VERSION 5.7 ;
  NOWIREEXTENSIONATPIN ON ;
  DIVIDERCHAR "/" ;
  BUSBITCHARS "[]" ;
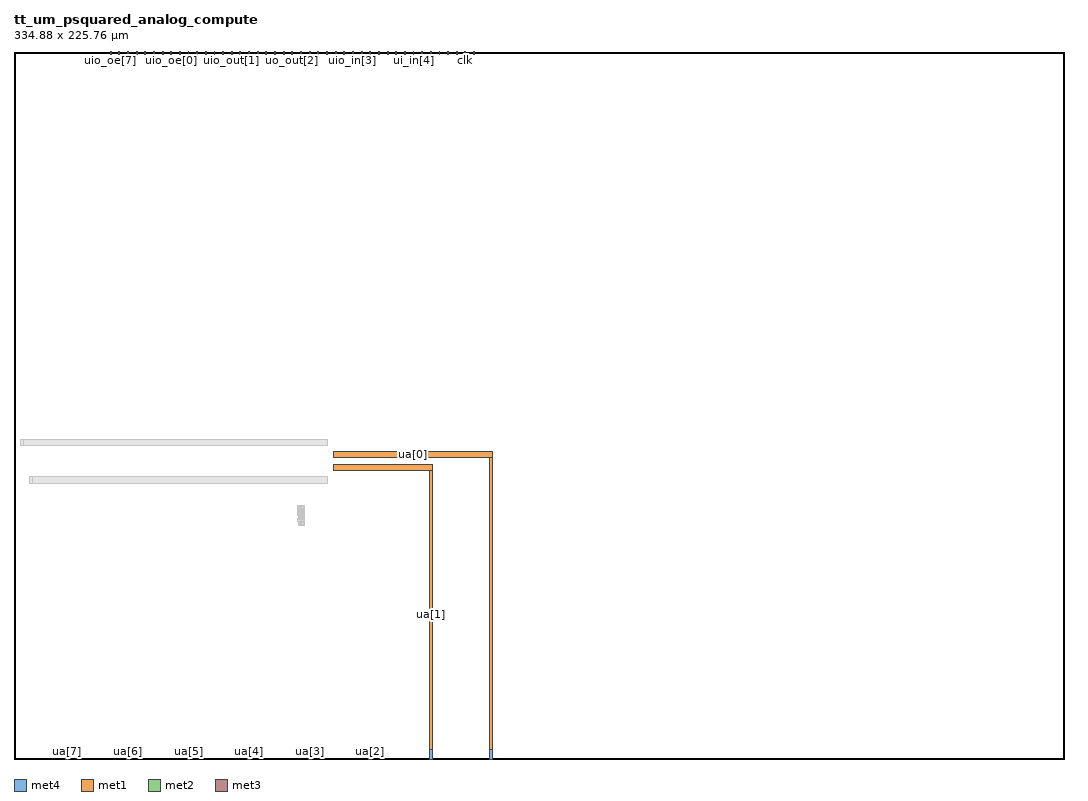
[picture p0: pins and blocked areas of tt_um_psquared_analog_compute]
MACRO tt_um_psquared_analog_compute
  CLASS BLOCK ;
  FOREIGN tt_um_psquared_analog_compute ;
  ORIGIN 0.000 0.000 ;
  SIZE 334.880 BY 225.760 ;
  PIN clk
    DIRECTION INPUT ;
    USE SIGNAL ;
    PORT
      LAYER met4 ;
        RECT 143.830 224.760 144.130 225.760 ;
    END
  END clk
  PIN ena
    DIRECTION INPUT ;
    USE SIGNAL ;
    PORT
      LAYER met4 ;
        RECT 146.590 224.760 146.890 225.760 ;
    END
  END ena
  PIN rst_n
    DIRECTION INPUT ;
    USE SIGNAL ;
    PORT
      LAYER met4 ;
        RECT 141.070 224.760 141.370 225.760 ;
    END
  END rst_n
  PIN ua[0]
    DIRECTION INOUT ;
    USE SIGNAL ;
    PORT
      LAYER met1 ;
        RECT 102.000 96.000 152.710 98.000 ;
        RECT 151.810 0.000 152.710 96.000 ;
      LAYER met2 ;
        RECT 151.810 0.000 152.710 3.000 ;
      LAYER met3 ;
        RECT 151.810 0.000 152.710 3.000 ;
      LAYER met4 ;
        RECT 151.810 0.000 152.710 3.000 ;
    END
  END ua[0]
  PIN ua[1]
    DIRECTION INOUT ;
    USE SIGNAL ;
    PORT
      LAYER met1 ;
        RECT 102.000 92.000 133.390 94.000 ;
        RECT 132.490 0.000 133.390 92.000 ;
      LAYER met2 ;
        RECT 132.490 0.000 133.390 3.000 ;
      LAYER met3 ;
        RECT 132.490 0.000 133.390 3.000 ;
      LAYER met4 ;
        RECT 132.490 0.000 133.390 3.000 ;
    END
  END ua[1]
  PIN ua[2]
    DIRECTION INOUT ;
    USE SIGNAL ;
    PORT
      LAYER met4 ;
        RECT 113.170 0.000 114.070 1.000 ;
    END
  END ua[2]
  PIN ua[3]
    DIRECTION INOUT ;
    USE SIGNAL ;
    PORT
      LAYER met4 ;
        RECT 93.850 0.000 94.750 1.000 ;
    END
  END ua[3]
  PIN ua[4]
    DIRECTION INOUT ;
    USE SIGNAL ;
    PORT
      LAYER met4 ;
        RECT 74.530 0.000 75.430 1.000 ;
    END
  END ua[4]
  PIN ua[5]
    DIRECTION INOUT ;
    USE SIGNAL ;
    PORT
      LAYER met4 ;
        RECT 55.210 0.000 56.110 1.000 ;
    END
  END ua[5]
  PIN ua[6]
    DIRECTION INOUT ;
    USE SIGNAL ;
    PORT
      LAYER met4 ;
        RECT 35.890 0.000 36.790 1.000 ;
    END
  END ua[6]
  PIN ua[7]
    DIRECTION INOUT ;
    USE SIGNAL ;
    PORT
      LAYER met4 ;
        RECT 16.570 0.000 17.470 1.000 ;
    END
  END ua[7]
  PIN ui_in[0]
    DIRECTION INPUT ;
    USE SIGNAL ;
    PORT
      LAYER met4 ;
        RECT 138.310 224.760 138.610 225.760 ;
    END
  END ui_in[0]
  PIN ui_in[1]
    DIRECTION INPUT ;
    USE SIGNAL ;
    PORT
      LAYER met4 ;
        RECT 135.550 224.760 135.850 225.760 ;
    END
  END ui_in[1]
  PIN ui_in[2]
    DIRECTION INPUT ;
    USE SIGNAL ;
    PORT
      LAYER met4 ;
        RECT 132.790 224.760 133.090 225.760 ;
    END
  END ui_in[2]
  PIN ui_in[3]
    DIRECTION INPUT ;
    USE SIGNAL ;
    PORT
      LAYER met4 ;
        RECT 130.030 224.760 130.330 225.760 ;
    END
  END ui_in[3]
  PIN ui_in[4]
    DIRECTION INPUT ;
    USE SIGNAL ;
    PORT
      LAYER met4 ;
        RECT 127.270 224.760 127.570 225.760 ;
    END
  END ui_in[4]
  PIN ui_in[5]
    DIRECTION INPUT ;
    USE SIGNAL ;
    PORT
      LAYER met4 ;
        RECT 124.510 224.760 124.810 225.760 ;
    END
  END ui_in[5]
  PIN ui_in[6]
    DIRECTION INPUT ;
    USE SIGNAL ;
    PORT
      LAYER met4 ;
        RECT 121.750 224.760 122.050 225.760 ;
    END
  END ui_in[6]
  PIN ui_in[7]
    DIRECTION INPUT ;
    USE SIGNAL ;
    PORT
      LAYER met4 ;
        RECT 118.990 224.760 119.290 225.760 ;
    END
  END ui_in[7]
  PIN uio_in[0]
    DIRECTION INPUT ;
    USE SIGNAL ;
    PORT
      LAYER met4 ;
        RECT 116.230 224.760 116.530 225.760 ;
    END
  END uio_in[0]
  PIN uio_in[1]
    DIRECTION INPUT ;
    USE SIGNAL ;
    PORT
      LAYER met4 ;
        RECT 113.470 224.760 113.770 225.760 ;
    END
  END uio_in[1]
  PIN uio_in[2]
    DIRECTION INPUT ;
    USE SIGNAL ;
    PORT
      LAYER met4 ;
        RECT 110.710 224.760 111.010 225.760 ;
    END
  END uio_in[2]
  PIN uio_in[3]
    DIRECTION INPUT ;
    USE SIGNAL ;
    PORT
      LAYER met4 ;
        RECT 107.950 224.760 108.250 225.760 ;
    END
  END uio_in[3]
  PIN uio_in[4]
    DIRECTION INPUT ;
    USE SIGNAL ;
    PORT
      LAYER met4 ;
        RECT 105.190 224.760 105.490 225.760 ;
    END
  END uio_in[4]
  PIN uio_in[5]
    DIRECTION INPUT ;
    USE SIGNAL ;
    PORT
      LAYER met4 ;
        RECT 102.430 224.760 102.730 225.760 ;
    END
  END uio_in[5]
  PIN uio_in[6]
    DIRECTION INPUT ;
    USE SIGNAL ;
    PORT
      LAYER met4 ;
        RECT 99.670 224.760 99.970 225.760 ;
    END
  END uio_in[6]
  PIN uio_in[7]
    DIRECTION INPUT ;
    USE SIGNAL ;
    PORT
      LAYER met4 ;
        RECT 96.910 224.760 97.210 225.760 ;
    END
  END uio_in[7]
  PIN uio_oe[0]
    DIRECTION OUTPUT ;
    USE SIGNAL ;
    PORT
      LAYER met4 ;
        RECT 49.990 224.760 50.290 225.760 ;
    END
  END uio_oe[0]
  PIN uio_oe[1]
    DIRECTION OUTPUT ;
    USE SIGNAL ;
    PORT
      LAYER met4 ;
        RECT 47.230 224.760 47.530 225.760 ;
    END
  END uio_oe[1]
  PIN uio_oe[2]
    DIRECTION OUTPUT ;
    USE SIGNAL ;
    PORT
      LAYER met4 ;
        RECT 44.470 224.760 44.770 225.760 ;
    END
  END uio_oe[2]
  PIN uio_oe[3]
    DIRECTION OUTPUT ;
    USE SIGNAL ;
    PORT
      LAYER met4 ;
        RECT 41.710 224.760 42.010 225.760 ;
    END
  END uio_oe[3]
  PIN uio_oe[4]
    DIRECTION OUTPUT ;
    USE SIGNAL ;
    PORT
      LAYER met4 ;
        RECT 38.950 224.760 39.250 225.760 ;
    END
  END uio_oe[4]
  PIN uio_oe[5]
    DIRECTION OUTPUT ;
    USE SIGNAL ;
    PORT
      LAYER met4 ;
        RECT 36.190 224.760 36.490 225.760 ;
    END
  END uio_oe[5]
  PIN uio_oe[6]
    DIRECTION OUTPUT ;
    USE SIGNAL ;
    PORT
      LAYER met4 ;
        RECT 33.430 224.760 33.730 225.760 ;
    END
  END uio_oe[6]
  PIN uio_oe[7]
    DIRECTION OUTPUT ;
    USE SIGNAL ;
    PORT
      LAYER met4 ;
        RECT 30.670 224.760 30.970 225.760 ;
    END
  END uio_oe[7]
  PIN uio_out[0]
    DIRECTION OUTPUT ;
    USE SIGNAL ;
    PORT
      LAYER met4 ;
        RECT 72.070 224.760 72.370 225.760 ;
    END
  END uio_out[0]
  PIN uio_out[1]
    DIRECTION OUTPUT ;
    USE SIGNAL ;
    PORT
      LAYER met4 ;
        RECT 69.310 224.760 69.610 225.760 ;
    END
  END uio_out[1]
  PIN uio_out[2]
    DIRECTION OUTPUT ;
    USE SIGNAL ;
    PORT
      LAYER met4 ;
        RECT 66.550 224.760 66.850 225.760 ;
    END
  END uio_out[2]
  PIN uio_out[3]
    DIRECTION OUTPUT ;
    USE SIGNAL ;
    PORT
      LAYER met4 ;
        RECT 63.790 224.760 64.090 225.760 ;
    END
  END uio_out[3]
  PIN uio_out[4]
    DIRECTION OUTPUT ;
    USE SIGNAL ;
    PORT
      LAYER met4 ;
        RECT 61.030 224.760 61.330 225.760 ;
    END
  END uio_out[4]
  PIN uio_out[5]
    DIRECTION OUTPUT ;
    USE SIGNAL ;
    PORT
      LAYER met4 ;
        RECT 58.270 224.760 58.570 225.760 ;
    END
  END uio_out[5]
  PIN uio_out[6]
    DIRECTION OUTPUT ;
    USE SIGNAL ;
    PORT
      LAYER met4 ;
        RECT 55.510 224.760 55.810 225.760 ;
    END
  END uio_out[6]
  PIN uio_out[7]
    DIRECTION OUTPUT ;
    USE SIGNAL ;
    PORT
      LAYER met4 ;
        RECT 52.750 224.760 53.050 225.760 ;
    END
  END uio_out[7]
  PIN uo_out[0]
    DIRECTION OUTPUT ;
    USE SIGNAL ;
    PORT
      LAYER met4 ;
        RECT 94.150 224.760 94.450 225.760 ;
    END
  END uo_out[0]
  PIN uo_out[1]
    DIRECTION OUTPUT ;
    USE SIGNAL ;
    PORT
      LAYER met4 ;
        RECT 91.390 224.760 91.690 225.760 ;
    END
  END uo_out[1]
  PIN uo_out[2]
    DIRECTION OUTPUT ;
    USE SIGNAL ;
    PORT
      LAYER met4 ;
        RECT 88.630 224.760 88.930 225.760 ;
    END
  END uo_out[2]
  PIN uo_out[3]
    DIRECTION OUTPUT ;
    USE SIGNAL ;
    PORT
      LAYER met4 ;
        RECT 85.870 224.760 86.170 225.760 ;
    END
  END uo_out[3]
  PIN uo_out[4]
    DIRECTION OUTPUT ;
    USE SIGNAL ;
    PORT
      LAYER met4 ;
        RECT 83.110 224.760 83.410 225.760 ;
    END
  END uo_out[4]
  PIN uo_out[5]
    DIRECTION OUTPUT ;
    USE SIGNAL ;
    PORT
      LAYER met4 ;
        RECT 80.350 224.760 80.650 225.760 ;
    END
  END uo_out[5]
  PIN uo_out[6]
    DIRECTION OUTPUT ;
    USE SIGNAL ;
    PORT
      LAYER met4 ;
        RECT 77.590 224.760 77.890 225.760 ;
    END
  END uo_out[6]
  PIN uo_out[7]
    DIRECTION OUTPUT ;
    USE SIGNAL ;
    PORT
      LAYER met4 ;
        RECT 74.830 224.760 75.130 225.760 ;
    END
  END uo_out[7]
  OBS
      LAYER nwell ;
        RECT 90.570 77.700 92.680 80.890 ;
      LAYER pwell ;
        RECT 90.620 74.340 92.630 77.340 ;
      LAYER li1 ;
        RECT 90.750 80.540 92.500 80.710 ;
        RECT 90.750 78.050 90.920 80.540 ;
        RECT 91.460 80.030 91.790 80.200 ;
        RECT 91.320 78.775 91.490 79.815 ;
        RECT 91.760 78.775 91.930 79.815 ;
        RECT 91.460 78.390 91.790 78.560 ;
        RECT 92.330 78.050 92.500 80.540 ;
        RECT 90.750 77.880 92.500 78.050 ;
        RECT 90.750 77.040 92.500 77.210 ;
        RECT 90.750 76.340 90.920 77.040 ;
        RECT 91.460 76.530 91.790 76.700 ;
        RECT 90.750 75.830 90.930 76.340 ;
        RECT 90.750 74.640 90.920 75.830 ;
        RECT 91.320 75.320 91.490 76.360 ;
        RECT 91.760 75.320 91.930 76.360 ;
        RECT 91.460 74.980 91.790 75.150 ;
        RECT 92.330 74.640 92.500 77.040 ;
        RECT 90.750 74.470 92.500 74.640 ;
      LAYER met1 ;
        RECT 2.000 100.000 100.000 102.000 ;
        RECT 5.000 88.000 100.000 90.000 ;
        RECT 91.450 80.010 91.840 80.300 ;
        RECT 91.480 80.000 91.770 80.010 ;
        RECT 90.680 79.310 91.070 79.400 ;
        RECT 91.290 79.310 91.520 79.795 ;
        RECT 90.680 78.795 91.520 79.310 ;
        RECT 91.730 79.310 91.960 79.795 ;
        RECT 91.730 78.795 92.350 79.310 ;
        RECT 90.680 78.790 91.390 78.795 ;
        RECT 91.770 78.790 92.350 78.795 ;
        RECT 90.680 78.750 91.010 78.790 ;
        RECT 91.480 78.560 91.770 78.590 ;
        RECT 90.560 76.340 91.040 76.550 ;
        RECT 91.460 76.530 91.790 78.560 ;
        RECT 91.480 76.500 91.770 76.530 ;
        RECT 92.060 76.340 92.350 78.790 ;
        RECT 90.560 75.820 91.520 76.340 ;
        RECT 90.560 75.670 91.040 75.820 ;
        RECT 91.290 75.340 91.520 75.820 ;
        RECT 91.730 75.790 92.350 76.340 ;
        RECT 91.730 75.340 91.960 75.790 ;
        RECT 91.480 75.160 91.770 75.180 ;
        RECT 91.450 74.870 91.840 75.160 ;
      LAYER met2 ;
        RECT 2.000 100.000 3.000 102.000 ;
        RECT 5.000 88.000 6.000 90.000 ;
      LAYER met3 ;
        RECT 2.000 100.000 3.000 102.000 ;
        RECT 5.000 88.000 6.000 90.000 ;
      LAYER met4 ;
        RECT 2.000 100.000 3.000 102.000 ;
        RECT 5.000 88.000 6.000 90.000 ;
  END
END tt_um_psquared_analog_compute
END LIBRARY

